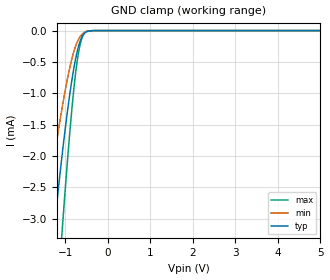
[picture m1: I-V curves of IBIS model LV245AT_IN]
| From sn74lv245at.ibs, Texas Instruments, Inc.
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[Model]   LV245AT_IN
Model_type  Input
Vinl=0.8
Vinh=2.0
| variable   typ   min   max
C_comp   1.02pF   0.86pF   1.11pF
[Temperature Range]   40   100   -40
| Ambient temperature   25   85   -40
[Voltage range]   5   4.5   5.5
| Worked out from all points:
|   GND clamp passes 1 mA (typ) near -0.89 V on its own axis
[GND Clamp]
| LV245AT_IN
|   Voltage   I(typ)   I(min)   I(max)
-5V       -39.32mA   -26.43mA   -50.15mA
-1.54V    -5.154mA   -3.362mA   -7.962mA
-1.49V    -4.776mA   -3.109mA   -7.418mA
-1.28V    -3.276mA   -2.101mA   -5.202mA
-1.25V    -3.075mA   -1.965mA   -4.896mA
-1.08V    -2.002mA   -1.243mA   -3.23mA
-900mV    -1.03mA    -601.4uA   -1.652mA
-775mV    -504uA     -279.4uA   -767.4uA
-720mV    -327.9uA   -180.7uA   -472.4uA
-660mV    -182.1uA   -103.4uA   -239.4uA
-540mV    -34.71uA   -23.96uA   -34.43uA
5V        17.64nA    1.142nA    163.4nA
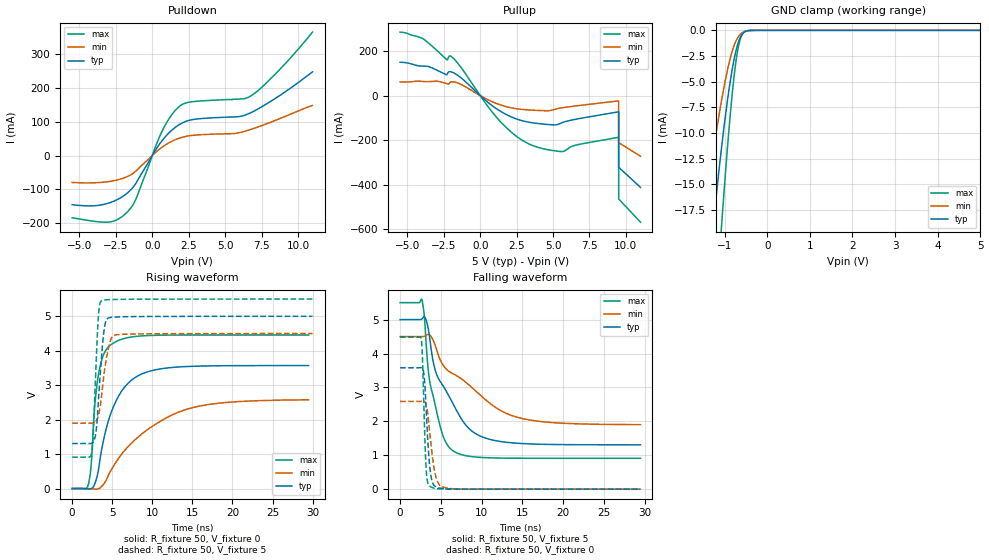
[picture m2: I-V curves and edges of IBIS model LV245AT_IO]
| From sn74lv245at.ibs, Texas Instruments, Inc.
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[Model]   LV245AT_IO
Model_type  I/O
Vinl=0.8
Vinh=2.0
Enable   Active-Low
Vref =   5
Rref =   1000
Cref =   50p
Vmeas =   1.5
| variable   typ   min   max
C_comp   4.88pF   3.72pF   5.69pF
| C_pullup   7.66pF   3.96pF   12.44pF
| C_pulldown   7.49pF   4.55pF   12.28pF
| C_tri-state   4.88pF   3.72pF   5.69pF
[Temperature Range]   40   100   -40
| Ambient temperature   25   85   -40
[Voltage range]   5   4.5   5.5
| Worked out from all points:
|   slope of the pulldown table from 0 to 0.75 V, typ, clamps not added: 15.5 ohm
|   slope of the pullup table from 0 to 0.75 V, typ, clamps not added: 18 ohm
|   GND clamp passes 1 mA (typ) near -0.66 V on its own axis
|   rising waveform, R_fixture 50, V_fixture 0: 20-80 % time 2.86ns typ, 7.02ns min, 1.07ns max; typ from 0 V to 3.57 V
|   falling waveform, R_fixture 50, V_fixture 5: 20-80 % time 3.86ns typ, 7ns min, 1.82ns max; typ from 5 V to 1.31 V
|   rising waveform, R_fixture 50, V_fixture 5: 20-80 % time 687ps typ, 923ps min, 489ps max; typ from 1.31 V to 5 V
|   falling waveform, R_fixture 50, V_fixture 0: 20-80 % time 529ps typ, 781ps min, 347ps max; typ from 3.58 V to 0 V
[GND Clamp]
| LV245AT_IO
|   Voltage   I(typ)   I(min)   I(max)
-5V       -249.2mA   -164mA     -317.6mA
-1.505V   -29.59mA   -18.74mA   -46.96mA
-1.275V   -19.38mA   -12.05mA   -31.64mA
-1.25V    -18.34mA   -11.37mA   -30.04mA
-1.075V   -11.59mA   -6.938mA   -19.32mA
-1.055V   -10.88mA   -6.474mA   -18.16mA
-880mV    -5.336mA   -2.947mA   -8.852mA
-770mV    -2.694mA   -1.41mA    -4.239mA
-670mV    -1.088mA   -578.2uA   -1.483mA
-620mV    -595.3uA   -340uA     -724.8uA
-550mV    -210.2uA   -143.8uA   -211.8uA
5V        86.46nA    5.749nA    824.4nA
[Pulldown]
| LV245AT_IO
|   Voltage   I(typ)   I(min)   I(max)
-5.5V     -145.4mA   -79.52mA   -183.9mA
-3.12V    -142.2mA   -77.7mA    -197.1mA
-2.03V    -121mA     -67.55mA   -179.1mA
-1.225V   -88.4mA    -49.59mA   -138.2mA
565mV     37.98mA    21.25mA    62.24mA
1.135V    66.8mA     37.52mA    108mA
1.73V     88.12mA    49.51mA    140.5mA
2.6V      104.9mA    58.91mA    158.3mA
5.62V     114.3mA    65.19mA    166.4mA
6.68V     125.1mA    76.12mA    174.3mA
8.57V     172.4mA    106.1mA    246.6mA
11V       247.6mA    148.4mA    365.2mA
[Pullup]
| LV245AT_IO
|   Voltage   I(typ)   I(min)   I(max)
-5.5V     150mA      61.5mA     285.3mA
-3.955V   132.6mA    63.6mA     256.8mA
-2.28V    94.75mA    53.83mA    160.7mA
-2.105V   107.3mA    56.59mA    178mA
-1.905V   104.7mA    62.32mA    171.4mA
1.215V    -63.15mA   -37.92mA   -104.5mA
3.32V     -119.2mA   -64.31mA   -216.3mA
5.625V    -121.6mA   -54.64mA   -251.3mA
6.545V    -106.3mA   -46.49mA   -222.6mA
9.5V      -72.63mA   -23.53mA   -187.2mA
9.505V    -322.1mA   -211.4mA   -464.5mA
11V       -412.5mA   -272.3mA   -568.6mA
[Ramp]
| LV245AT_IO
| variable   typ   min   max
dV/dt_r   2.15/2.86E-09   1.56/7.02E-09   2.68/1.07E-09
dV/dt_f   2.27/3.85E-09   1.60/6.99E-09   2.82/1.82E-09
R_load = 50
[Rising Waveform]
| LV245AT_IO
R_fixture =   50
C_fixture =   0
L_fixture =   0
V_fixture =   0
V_fixture_min = 0
V_fixture_max = 0
|   Time   V(typ)   V(min)   V(max)
0s        37.52nV    5.475nV    454.2nV
2.01ns    -11.6mV    178uV      108.4mV
2.335ns   -8.57mV    -4.171mV   590.1mV
2.815ns   132.3mV    -15.93mV   2.386V
3.295ns   564mV      -5.652mV   3.325V
4.005ns   1.502V     153.2mV    3.933V
5.1ns     2.345V     628.8mV    4.217V
8.07ns    3.253V     1.462V     4.418V
13.86ns   3.537V     2.269V     4.456V
29.5ns    3.569V     2.577V     4.457V
[Falling Waveform]
| LV245AT_IO
R_fixture =   50
C_fixture =   0
L_fixture =   0
V_fixture =   5
V_fixture_min = 4.5
V_fixture_max = 5.5
|   Time   V(typ)   V(min)   V(max)
0s        5V         4.5V       5.5V
2.67ns    5.016V     4.499V     5.59V
3.205ns   4.976V     4.539V     4.263V
3.74ns    4.254V     4.52V      3.044V
4.335ns   3.49V      4.222V     2.449V
5.24ns    3.061V     3.67V      1.589V
6.55ns    2.492V     3.398V     1.121V
8.6ns     1.755V     3.042V     966.5mV
11.44ns   1.444V     2.456V     921.2mV
29.5ns    1.308V     1.902V     910.3mV
[Rising Waveform]
| LV245AT_IO
R_fixture =   50
C_fixture =   0
L_fixture =   0
V_fixture =   5
V_fixture_min = 4.5
V_fixture_max = 5.5
|   Time   V(typ)   V(min)   V(max)
0s        1.308V     1.898V     910.3mV
2.43ns    1.312V     1.896V     1.044V
2.615ns   1.345V     1.896V     1.506V
2.925ns   1.573V     1.936V     3.26V
3.25ns    2.449V     2.099V     4.919V
3.66ns    3.817V     2.678V     5.452V
4.2ns     4.854V     3.674V     5.478V
4.765ns   4.965V     4.286V     5.485V
5.305ns   4.977V     4.454V     5.489V
29.99ns   5V         4.5V       5.5V
[Falling Waveform]
| LV245AT_IO
R_fixture =   50
C_fixture =   0
L_fixture =   0
V_fixture =   0
V_fixture_min = 0
V_fixture_max = 0
|   Time   V(typ)   V(min)   V(max)
0s        3.579V     2.588V     4.481V
2.58ns    3.584V     2.588V     4.435V
2.74ns    3.568V     2.591V     3.893V
2.93ns    3.374V     2.592V     2.365V
3.195ns   2.371V     2.494V     611.5mV
3.49ns    1.092V     2.015V     127mV
3.745ns   457.6mV    1.426V     72.11mV
4.445ns   67.91mV    322.3mV    15.92mV
5.53ns    12.12mV    41.83mV    3.472mV
29.5ns    918.7nV    10.11uV    474.1nV
